VERSION 5.6 ;
BUSBITCHARS "[]" ;
DIVIDERCHAR "/" ;

# Cells with signal pins on metal4 and metal3 respectively.
# Used to test that fillVIA creates a via stack when two pins from
# different cells land in the same gcell on different routing layers.

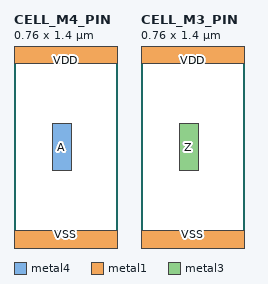
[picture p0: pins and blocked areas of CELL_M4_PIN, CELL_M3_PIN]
MACRO CELL_M4_PIN
  CLASS CORE ;
  ORIGIN 0 0 ;
  FOREIGN CELL_M4_PIN 0 0 ;
  SIZE 0.76 BY 1.4 ;
  SYMMETRY X Y ;
  SITE FreePDK45_38x28_10R_NP_162NW_34O ;
  PIN A
    DIRECTION INPUT ;
    USE SIGNAL ;
    PORT
      LAYER metal4 ;
        RECT 0.28 0.525 0.42 0.875 ;
    END
  END A
  PIN VDD
    DIRECTION INOUT ;
    USE POWER ;
    SHAPE ABUTMENT ;
    PORT
      LAYER metal1 ;
        RECT 0 1.315 0.76 1.485 ;
    END
  END VDD
  PIN VSS
    DIRECTION INOUT ;
    USE GROUND ;
    SHAPE ABUTMENT ;
    PORT
      LAYER metal1 ;
        RECT 0 -0.085 0.76 0.085 ;
    END
  END VSS
END CELL_M4_PIN

MACRO CELL_M3_PIN
  CLASS CORE ;
  ORIGIN 0 0 ;
  FOREIGN CELL_M3_PIN 0 0 ;
  SIZE 0.76 BY 1.4 ;
  SYMMETRY X Y ;
  SITE FreePDK45_38x28_10R_NP_162NW_34O ;
  PIN Z
    DIRECTION OUTPUT ;
    USE SIGNAL ;
    PORT
      LAYER metal3 ;
        RECT 0.28 0.525 0.42 0.875 ;
    END
  END Z
  PIN VDD
    DIRECTION INOUT ;
    USE POWER ;
    SHAPE ABUTMENT ;
    PORT
      LAYER metal1 ;
        RECT 0 1.315 0.76 1.485 ;
    END
  END VDD
  PIN VSS
    DIRECTION INOUT ;
    USE GROUND ;
    SHAPE ABUTMENT ;
    PORT
      LAYER metal1 ;
        RECT 0 -0.085 0.76 0.085 ;
    END
  END VSS
END CELL_M3_PIN

END LIBRARY
